VERSION 5.7 ;
  NOWIREEXTENSIONATPIN ON ;
  DIVIDERCHAR "/" ;
  BUSBITCHARS "[]" ;
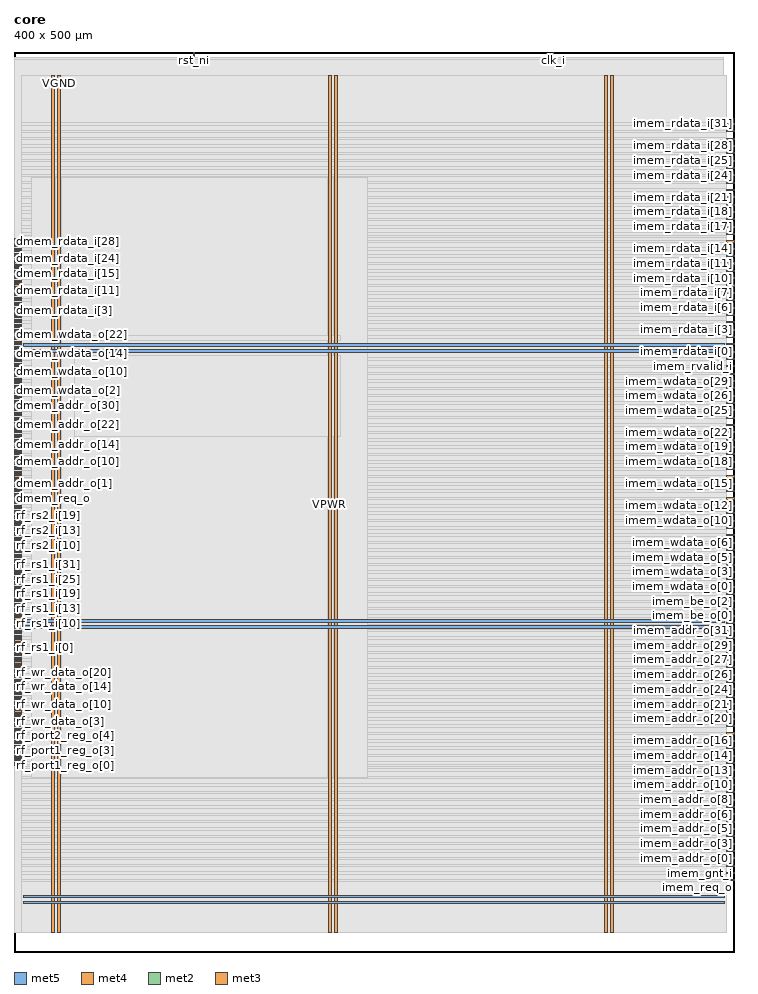
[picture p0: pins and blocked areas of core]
MACRO core
  CLASS BLOCK ;
  FOREIGN core ;
  ORIGIN 0.000 0.000 ;
  SIZE 400.000 BY 500.000 ;
  PIN VGND
    USE GROUND ;
    PORT
      LAYER met5 ;
        RECT 5.280 336.390 394.460 337.990 ;
    END
    PORT
      LAYER met5 ;
        RECT 5.280 183.210 394.460 184.810 ;
    END
    PORT
      LAYER met5 ;
        RECT 5.280 30.030 394.460 31.630 ;
    END
    PORT
      LAYER met4 ;
        RECT 331.540 10.640 333.140 487.120 ;
    END
    PORT
      LAYER met4 ;
        RECT 177.940 10.640 179.540 487.120 ;
    END
    PORT
      LAYER met4 ;
        RECT 24.340 10.640 25.940 487.120 ;
    END
  END VGND
  PIN VPWR
    USE POWER ;
    PORT
      LAYER met5 ;
        RECT 5.280 333.090 394.460 334.690 ;
    END
    PORT
      LAYER met5 ;
        RECT 5.280 179.910 394.460 181.510 ;
    END
    PORT
      LAYER met5 ;
        RECT 5.280 26.730 394.460 28.330 ;
    END
    PORT
      LAYER met4 ;
        RECT 328.240 10.640 329.840 487.120 ;
    END
    PORT
      LAYER met4 ;
        RECT 174.640 10.640 176.240 487.120 ;
    END
    PORT
      LAYER met4 ;
        RECT 21.040 10.640 22.640 487.120 ;
    END
  END VPWR
  PIN clk_i
    PORT
      LAYER met2 ;
        RECT 299.550 496.000 299.830 500.000 ;
    END
  END clk_i
  PIN dmem_addr_o[0]
    PORT
      LAYER met3 ;
        RECT 0.000 258.440 4.000 259.040 ;
    END
  END dmem_addr_o[0]
  PIN dmem_addr_o[10]
    PORT
      LAYER met3 ;
        RECT 0.000 272.040 4.000 272.640 ;
    END
  END dmem_addr_o[10]
  PIN dmem_addr_o[11]
    PORT
      LAYER met3 ;
        RECT 0.000 273.400 4.000 274.000 ;
    END
  END dmem_addr_o[11]
  PIN dmem_addr_o[12]
    PORT
      LAYER met3 ;
        RECT 0.000 274.760 4.000 275.360 ;
    END
  END dmem_addr_o[12]
  PIN dmem_addr_o[13]
    PORT
      LAYER met3 ;
        RECT 0.000 276.120 4.000 276.720 ;
    END
  END dmem_addr_o[13]
  PIN dmem_addr_o[14]
    PORT
      LAYER met3 ;
        RECT 0.000 277.480 4.000 278.080 ;
    END
  END dmem_addr_o[14]
  PIN dmem_addr_o[15]
    PORT
      LAYER met3 ;
        RECT 0.000 278.840 4.000 279.440 ;
    END
  END dmem_addr_o[15]
  PIN dmem_addr_o[16]
    PORT
      LAYER met3 ;
        RECT 0.000 280.200 4.000 280.800 ;
    END
  END dmem_addr_o[16]
  PIN dmem_addr_o[17]
    PORT
      LAYER met3 ;
        RECT 0.000 281.560 4.000 282.160 ;
    END
  END dmem_addr_o[17]
  PIN dmem_addr_o[18]
    PORT
      LAYER met3 ;
        RECT 0.000 282.920 4.000 283.520 ;
    END
  END dmem_addr_o[18]
  PIN dmem_addr_o[19]
    PORT
      LAYER met3 ;
        RECT 0.000 284.280 4.000 284.880 ;
    END
  END dmem_addr_o[19]
  PIN dmem_addr_o[1]
    PORT
      LAYER met3 ;
        RECT 0.000 259.800 4.000 260.400 ;
    END
  END dmem_addr_o[1]
  PIN dmem_addr_o[20]
    PORT
      LAYER met3 ;
        RECT 0.000 285.640 4.000 286.240 ;
    END
  END dmem_addr_o[20]
  PIN dmem_addr_o[21]
    PORT
      LAYER met3 ;
        RECT 0.000 287.000 4.000 287.600 ;
    END
  END dmem_addr_o[21]
  PIN dmem_addr_o[22]
    PORT
      LAYER met3 ;
        RECT 0.000 288.360 4.000 288.960 ;
    END
  END dmem_addr_o[22]
  PIN dmem_addr_o[23]
    PORT
      LAYER met3 ;
        RECT 0.000 289.720 4.000 290.320 ;
    END
  END dmem_addr_o[23]
  PIN dmem_addr_o[24]
    PORT
      LAYER met3 ;
        RECT 0.000 291.080 4.000 291.680 ;
    END
  END dmem_addr_o[24]
  PIN dmem_addr_o[25]
    PORT
      LAYER met3 ;
        RECT 0.000 292.440 4.000 293.040 ;
    END
  END dmem_addr_o[25]
  PIN dmem_addr_o[26]
    PORT
      LAYER met3 ;
        RECT 0.000 293.800 4.000 294.400 ;
    END
  END dmem_addr_o[26]
  PIN dmem_addr_o[27]
    PORT
      LAYER met3 ;
        RECT 0.000 295.160 4.000 295.760 ;
    END
  END dmem_addr_o[27]
  PIN dmem_addr_o[28]
    PORT
      LAYER met3 ;
        RECT 0.000 296.520 4.000 297.120 ;
    END
  END dmem_addr_o[28]
  PIN dmem_addr_o[29]
    PORT
      LAYER met3 ;
        RECT 0.000 297.880 4.000 298.480 ;
    END
  END dmem_addr_o[29]
  PIN dmem_addr_o[2]
    PORT
      LAYER met3 ;
        RECT 0.000 261.160 4.000 261.760 ;
    END
  END dmem_addr_o[2]
  PIN dmem_addr_o[30]
    PORT
      LAYER met3 ;
        RECT 0.000 299.240 4.000 299.840 ;
    END
  END dmem_addr_o[30]
  PIN dmem_addr_o[31]
    PORT
      LAYER met3 ;
        RECT 0.000 300.600 4.000 301.200 ;
    END
  END dmem_addr_o[31]
  PIN dmem_addr_o[3]
    PORT
      LAYER met3 ;
        RECT 0.000 262.520 4.000 263.120 ;
    END
  END dmem_addr_o[3]
  PIN dmem_addr_o[4]
    PORT
      LAYER met3 ;
        RECT 0.000 263.880 4.000 264.480 ;
    END
  END dmem_addr_o[4]
  PIN dmem_addr_o[5]
    PORT
      LAYER met3 ;
        RECT 0.000 265.240 4.000 265.840 ;
    END
  END dmem_addr_o[5]
  PIN dmem_addr_o[6]
    PORT
      LAYER met3 ;
        RECT 0.000 266.600 4.000 267.200 ;
    END
  END dmem_addr_o[6]
  PIN dmem_addr_o[7]
    PORT
      LAYER met3 ;
        RECT 0.000 267.960 4.000 268.560 ;
    END
  END dmem_addr_o[7]
  PIN dmem_addr_o[8]
    PORT
      LAYER met3 ;
        RECT 0.000 269.320 4.000 269.920 ;
    END
  END dmem_addr_o[8]
  PIN dmem_addr_o[9]
    PORT
      LAYER met3 ;
        RECT 0.000 270.680 4.000 271.280 ;
    END
  END dmem_addr_o[9]
  PIN dmem_be_o[0]
    PORT
      LAYER met3 ;
        RECT 0.000 303.320 4.000 303.920 ;
    END
  END dmem_be_o[0]
  PIN dmem_be_o[1]
    PORT
      LAYER met3 ;
        RECT 0.000 304.680 4.000 305.280 ;
    END
  END dmem_be_o[1]
  PIN dmem_be_o[2]
    PORT
      LAYER met3 ;
        RECT 0.000 306.040 4.000 306.640 ;
    END
  END dmem_be_o[2]
  PIN dmem_be_o[3]
    PORT
      LAYER met3 ;
        RECT 0.000 307.400 4.000 308.000 ;
    END
  END dmem_be_o[3]
  PIN dmem_gnt_i
    PORT
      LAYER met3 ;
        RECT 0.000 257.080 4.000 257.680 ;
    END
  END dmem_gnt_i
  PIN dmem_rdata_i[0]
    PORT
      LAYER met3 ;
        RECT 0.000 352.280 4.000 352.880 ;
    END
  END dmem_rdata_i[0]
  PIN dmem_rdata_i[10]
    PORT
      LAYER met3 ;
        RECT 0.000 365.880 4.000 366.480 ;
    END
  END dmem_rdata_i[10]
  PIN dmem_rdata_i[11]
    PORT
      LAYER met3 ;
        RECT 0.000 367.240 4.000 367.840 ;
    END
  END dmem_rdata_i[11]
  PIN dmem_rdata_i[12]
    PORT
      LAYER met3 ;
        RECT 0.000 368.600 4.000 369.200 ;
    END
  END dmem_rdata_i[12]
  PIN dmem_rdata_i[13]
    PORT
      LAYER met3 ;
        RECT 0.000 369.960 4.000 370.560 ;
    END
  END dmem_rdata_i[13]
  PIN dmem_rdata_i[14]
    PORT
      LAYER met3 ;
        RECT 0.000 371.320 4.000 371.920 ;
    END
  END dmem_rdata_i[14]
  PIN dmem_rdata_i[15]
    PORT
      LAYER met3 ;
        RECT 0.000 372.680 4.000 373.280 ;
    END
  END dmem_rdata_i[15]
  PIN dmem_rdata_i[16]
    PORT
      LAYER met3 ;
        RECT 0.000 374.040 4.000 374.640 ;
    END
  END dmem_rdata_i[16]
  PIN dmem_rdata_i[17]
    PORT
      LAYER met3 ;
        RECT 0.000 375.400 4.000 376.000 ;
    END
  END dmem_rdata_i[17]
  PIN dmem_rdata_i[18]
    PORT
      LAYER met3 ;
        RECT 0.000 376.760 4.000 377.360 ;
    END
  END dmem_rdata_i[18]
  PIN dmem_rdata_i[19]
    PORT
      LAYER met3 ;
        RECT 0.000 378.120 4.000 378.720 ;
    END
  END dmem_rdata_i[19]
  PIN dmem_rdata_i[1]
    PORT
      LAYER met3 ;
        RECT 0.000 353.640 4.000 354.240 ;
    END
  END dmem_rdata_i[1]
  PIN dmem_rdata_i[20]
    PORT
      LAYER met3 ;
        RECT 0.000 379.480 4.000 380.080 ;
    END
  END dmem_rdata_i[20]
  PIN dmem_rdata_i[21]
    PORT
      LAYER met3 ;
        RECT 0.000 380.840 4.000 381.440 ;
    END
  END dmem_rdata_i[21]
  PIN dmem_rdata_i[22]
    PORT
      LAYER met3 ;
        RECT 0.000 382.200 4.000 382.800 ;
    END
  END dmem_rdata_i[22]
  PIN dmem_rdata_i[23]
    PORT
      LAYER met3 ;
        RECT 0.000 383.560 4.000 384.160 ;
    END
  END dmem_rdata_i[23]
  PIN dmem_rdata_i[24]
    PORT
      LAYER met3 ;
        RECT 0.000 384.920 4.000 385.520 ;
    END
  END dmem_rdata_i[24]
  PIN dmem_rdata_i[25]
    PORT
      LAYER met3 ;
        RECT 0.000 386.280 4.000 386.880 ;
    END
  END dmem_rdata_i[25]
  PIN dmem_rdata_i[26]
    PORT
      LAYER met3 ;
        RECT 0.000 387.640 4.000 388.240 ;
    END
  END dmem_rdata_i[26]
  PIN dmem_rdata_i[27]
    PORT
      LAYER met3 ;
        RECT 0.000 389.000 4.000 389.600 ;
    END
  END dmem_rdata_i[27]
  PIN dmem_rdata_i[28]
    PORT
      LAYER met3 ;
        RECT 0.000 390.360 4.000 390.960 ;
    END
  END dmem_rdata_i[28]
  PIN dmem_rdata_i[29]
    PORT
      LAYER met3 ;
        RECT 0.000 391.720 4.000 392.320 ;
    END
  END dmem_rdata_i[29]
  PIN dmem_rdata_i[2]
    PORT
      LAYER met3 ;
        RECT 0.000 355.000 4.000 355.600 ;
    END
  END dmem_rdata_i[2]
  PIN dmem_rdata_i[30]
    PORT
      LAYER met3 ;
        RECT 0.000 393.080 4.000 393.680 ;
    END
  END dmem_rdata_i[30]
  PIN dmem_rdata_i[31]
    PORT
      LAYER met3 ;
        RECT 0.000 394.440 4.000 395.040 ;
    END
  END dmem_rdata_i[31]
  PIN dmem_rdata_i[3]
    PORT
      LAYER met3 ;
        RECT 0.000 356.360 4.000 356.960 ;
    END
  END dmem_rdata_i[3]
  PIN dmem_rdata_i[4]
    PORT
      LAYER met3 ;
        RECT 0.000 357.720 4.000 358.320 ;
    END
  END dmem_rdata_i[4]
  PIN dmem_rdata_i[5]
    PORT
      LAYER met3 ;
        RECT 0.000 359.080 4.000 359.680 ;
    END
  END dmem_rdata_i[5]
  PIN dmem_rdata_i[6]
    PORT
      LAYER met3 ;
        RECT 0.000 360.440 4.000 361.040 ;
    END
  END dmem_rdata_i[6]
  PIN dmem_rdata_i[7]
    PORT
      LAYER met3 ;
        RECT 0.000 361.800 4.000 362.400 ;
    END
  END dmem_rdata_i[7]
  PIN dmem_rdata_i[8]
    PORT
      LAYER met3 ;
        RECT 0.000 363.160 4.000 363.760 ;
    END
  END dmem_rdata_i[8]
  PIN dmem_rdata_i[9]
    PORT
      LAYER met3 ;
        RECT 0.000 364.520 4.000 365.120 ;
    END
  END dmem_rdata_i[9]
  PIN dmem_req_o
    PORT
      LAYER met3 ;
        RECT 0.000 255.720 4.000 256.320 ;
    END
  END dmem_req_o
  PIN dmem_rvalid_i
    PORT
      LAYER met3 ;
        RECT 0.000 395.800 4.000 396.400 ;
    END
  END dmem_rvalid_i
  PIN dmem_wdata_o[0]
    PORT
      LAYER met3 ;
        RECT 0.000 308.760 4.000 309.360 ;
    END
  END dmem_wdata_o[0]
  PIN dmem_wdata_o[10]
    PORT
      LAYER met3 ;
        RECT 0.000 322.360 4.000 322.960 ;
    END
  END dmem_wdata_o[10]
  PIN dmem_wdata_o[11]
    PORT
      LAYER met3 ;
        RECT 0.000 323.720 4.000 324.320 ;
    END
  END dmem_wdata_o[11]
  PIN dmem_wdata_o[12]
    PORT
      LAYER met3 ;
        RECT 0.000 325.080 4.000 325.680 ;
    END
  END dmem_wdata_o[12]
  PIN dmem_wdata_o[13]
    PORT
      LAYER met3 ;
        RECT 0.000 326.440 4.000 327.040 ;
    END
  END dmem_wdata_o[13]
  PIN dmem_wdata_o[14]
    PORT
      LAYER met3 ;
        RECT 0.000 327.800 4.000 328.400 ;
    END
  END dmem_wdata_o[14]
  PIN dmem_wdata_o[15]
    PORT
      LAYER met3 ;
        RECT 0.000 329.160 4.000 329.760 ;
    END
  END dmem_wdata_o[15]
  PIN dmem_wdata_o[16]
    PORT
      LAYER met3 ;
        RECT 0.000 330.520 4.000 331.120 ;
    END
  END dmem_wdata_o[16]
  PIN dmem_wdata_o[17]
    PORT
      LAYER met3 ;
        RECT 0.000 331.880 4.000 332.480 ;
    END
  END dmem_wdata_o[17]
  PIN dmem_wdata_o[18]
    PORT
      LAYER met3 ;
        RECT 0.000 333.240 4.000 333.840 ;
    END
  END dmem_wdata_o[18]
  PIN dmem_wdata_o[19]
    PORT
      LAYER met3 ;
        RECT 0.000 334.600 4.000 335.200 ;
    END
  END dmem_wdata_o[19]
  PIN dmem_wdata_o[1]
    PORT
      LAYER met3 ;
        RECT 0.000 310.120 4.000 310.720 ;
    END
  END dmem_wdata_o[1]
  PIN dmem_wdata_o[20]
    PORT
      LAYER met3 ;
        RECT 0.000 335.960 4.000 336.560 ;
    END
  END dmem_wdata_o[20]
  PIN dmem_wdata_o[21]
    PORT
      LAYER met3 ;
        RECT 0.000 337.320 4.000 337.920 ;
    END
  END dmem_wdata_o[21]
  PIN dmem_wdata_o[22]
    PORT
      LAYER met3 ;
        RECT 0.000 338.680 4.000 339.280 ;
    END
  END dmem_wdata_o[22]
  PIN dmem_wdata_o[23]
    PORT
      LAYER met3 ;
        RECT 0.000 340.040 4.000 340.640 ;
    END
  END dmem_wdata_o[23]
  PIN dmem_wdata_o[24]
    PORT
      LAYER met3 ;
        RECT 0.000 341.400 4.000 342.000 ;
    END
  END dmem_wdata_o[24]
  PIN dmem_wdata_o[25]
    PORT
      LAYER met3 ;
        RECT 0.000 342.760 4.000 343.360 ;
    END
  END dmem_wdata_o[25]
  PIN dmem_wdata_o[26]
    PORT
      LAYER met3 ;
        RECT 0.000 344.120 4.000 344.720 ;
    END
  END dmem_wdata_o[26]
  PIN dmem_wdata_o[27]
    PORT
      LAYER met3 ;
        RECT 0.000 345.480 4.000 346.080 ;
    END
  END dmem_wdata_o[27]
  PIN dmem_wdata_o[28]
    PORT
      LAYER met3 ;
        RECT 0.000 346.840 4.000 347.440 ;
    END
  END dmem_wdata_o[28]
  PIN dmem_wdata_o[29]
    PORT
      LAYER met3 ;
        RECT 0.000 348.200 4.000 348.800 ;
    END
  END dmem_wdata_o[29]
  PIN dmem_wdata_o[2]
    PORT
      LAYER met3 ;
        RECT 0.000 311.480 4.000 312.080 ;
    END
  END dmem_wdata_o[2]
  PIN dmem_wdata_o[30]
    PORT
      LAYER met3 ;
        RECT 0.000 349.560 4.000 350.160 ;
    END
  END dmem_wdata_o[30]
  PIN dmem_wdata_o[31]
    PORT
      LAYER met3 ;
        RECT 0.000 350.920 4.000 351.520 ;
    END
  END dmem_wdata_o[31]
  PIN dmem_wdata_o[3]
    PORT
      LAYER met3 ;
        RECT 0.000 312.840 4.000 313.440 ;
    END
  END dmem_wdata_o[3]
  PIN dmem_wdata_o[4]
    PORT
      LAYER met3 ;
        RECT 0.000 314.200 4.000 314.800 ;
    END
  END dmem_wdata_o[4]
  PIN dmem_wdata_o[5]
    PORT
      LAYER met3 ;
        RECT 0.000 315.560 4.000 316.160 ;
    END
  END dmem_wdata_o[5]
  PIN dmem_wdata_o[6]
    PORT
      LAYER met3 ;
        RECT 0.000 316.920 4.000 317.520 ;
    END
  END dmem_wdata_o[6]
  PIN dmem_wdata_o[7]
    PORT
      LAYER met3 ;
        RECT 0.000 318.280 4.000 318.880 ;
    END
  END dmem_wdata_o[7]
  PIN dmem_wdata_o[8]
    PORT
      LAYER met3 ;
        RECT 0.000 319.640 4.000 320.240 ;
    END
  END dmem_wdata_o[8]
  PIN dmem_wdata_o[9]
    PORT
      LAYER met3 ;
        RECT 0.000 321.000 4.000 321.600 ;
    END
  END dmem_wdata_o[9]
  PIN dmem_we_o
    PORT
      LAYER met3 ;
        RECT 0.000 301.960 4.000 302.560 ;
    END
  END dmem_we_o
  PIN imem_addr_o[0]
    PORT
      LAYER met3 ;
        RECT 396.000 47.640 400.000 48.240 ;
    END
  END imem_addr_o[0]
  PIN imem_addr_o[10]
    PORT
      LAYER met3 ;
        RECT 396.000 88.440 400.000 89.040 ;
    END
  END imem_addr_o[10]
  PIN imem_addr_o[11]
    PORT
      LAYER met3 ;
        RECT 396.000 92.520 400.000 93.120 ;
    END
  END imem_addr_o[11]
  PIN imem_addr_o[12]
    PORT
      LAYER met3 ;
        RECT 396.000 96.600 400.000 97.200 ;
    END
  END imem_addr_o[12]
  PIN imem_addr_o[13]
    PORT
      LAYER met3 ;
        RECT 396.000 100.680 400.000 101.280 ;
    END
  END imem_addr_o[13]
  PIN imem_addr_o[14]
    PORT
      LAYER met3 ;
        RECT 396.000 104.760 400.000 105.360 ;
    END
  END imem_addr_o[14]
  PIN imem_addr_o[15]
    PORT
      LAYER met3 ;
        RECT 396.000 108.840 400.000 109.440 ;
    END
  END imem_addr_o[15]
  PIN imem_addr_o[16]
    PORT
      LAYER met3 ;
        RECT 396.000 112.920 400.000 113.520 ;
    END
  END imem_addr_o[16]
  PIN imem_addr_o[17]
    PORT
      LAYER met3 ;
        RECT 396.000 117.000 400.000 117.600 ;
    END
  END imem_addr_o[17]
  PIN imem_addr_o[18]
    PORT
      LAYER met3 ;
        RECT 396.000 121.080 400.000 121.680 ;
    END
  END imem_addr_o[18]
  PIN imem_addr_o[19]
    PORT
      LAYER met3 ;
        RECT 396.000 125.160 400.000 125.760 ;
    END
  END imem_addr_o[19]
  PIN imem_addr_o[1]
    PORT
      LAYER met3 ;
        RECT 396.000 51.720 400.000 52.320 ;
    END
  END imem_addr_o[1]
  PIN imem_addr_o[20]
    PORT
      LAYER met3 ;
        RECT 396.000 129.240 400.000 129.840 ;
    END
  END imem_addr_o[20]
  PIN imem_addr_o[21]
    PORT
      LAYER met3 ;
        RECT 396.000 133.320 400.000 133.920 ;
    END
  END imem_addr_o[21]
  PIN imem_addr_o[22]
    PORT
      LAYER met3 ;
        RECT 396.000 137.400 400.000 138.000 ;
    END
  END imem_addr_o[22]
  PIN imem_addr_o[23]
    PORT
      LAYER met3 ;
        RECT 396.000 141.480 400.000 142.080 ;
    END
  END imem_addr_o[23]
  PIN imem_addr_o[24]
    PORT
      LAYER met3 ;
        RECT 396.000 145.560 400.000 146.160 ;
    END
  END imem_addr_o[24]
  PIN imem_addr_o[25]
    PORT
      LAYER met3 ;
        RECT 396.000 149.640 400.000 150.240 ;
    END
  END imem_addr_o[25]
  PIN imem_addr_o[26]
    PORT
      LAYER met3 ;
        RECT 396.000 153.720 400.000 154.320 ;
    END
  END imem_addr_o[26]
  PIN imem_addr_o[27]
    PORT
      LAYER met3 ;
        RECT 396.000 157.800 400.000 158.400 ;
    END
  END imem_addr_o[27]
  PIN imem_addr_o[28]
    PORT
      LAYER met3 ;
        RECT 396.000 161.880 400.000 162.480 ;
    END
  END imem_addr_o[28]
  PIN imem_addr_o[29]
    PORT
      LAYER met3 ;
        RECT 396.000 165.960 400.000 166.560 ;
    END
  END imem_addr_o[29]
  PIN imem_addr_o[2]
    PORT
      LAYER met3 ;
        RECT 396.000 55.800 400.000 56.400 ;
    END
  END imem_addr_o[2]
  PIN imem_addr_o[30]
    PORT
      LAYER met3 ;
        RECT 396.000 170.040 400.000 170.640 ;
    END
  END imem_addr_o[30]
  PIN imem_addr_o[31]
    PORT
      LAYER met3 ;
        RECT 396.000 174.120 400.000 174.720 ;
    END
  END imem_addr_o[31]
  PIN imem_addr_o[3]
    PORT
      LAYER met3 ;
        RECT 396.000 59.880 400.000 60.480 ;
    END
  END imem_addr_o[3]
  PIN imem_addr_o[4]
    PORT
      LAYER met3 ;
        RECT 396.000 63.960 400.000 64.560 ;
    END
  END imem_addr_o[4]
  PIN imem_addr_o[5]
    PORT
      LAYER met3 ;
        RECT 396.000 68.040 400.000 68.640 ;
    END
  END imem_addr_o[5]
  PIN imem_addr_o[6]
    PORT
      LAYER met3 ;
        RECT 396.000 72.120 400.000 72.720 ;
    END
  END imem_addr_o[6]
  PIN imem_addr_o[7]
    PORT
      LAYER met3 ;
        RECT 396.000 76.200 400.000 76.800 ;
    END
  END imem_addr_o[7]
  PIN imem_addr_o[8]
    PORT
      LAYER met3 ;
        RECT 396.000 80.280 400.000 80.880 ;
    END
  END imem_addr_o[8]
  PIN imem_addr_o[9]
    PORT
      LAYER met3 ;
        RECT 396.000 84.360 400.000 84.960 ;
    END
  END imem_addr_o[9]
  PIN imem_be_o[0]
    PORT
      LAYER met3 ;
        RECT 396.000 182.280 400.000 182.880 ;
    END
  END imem_be_o[0]
  PIN imem_be_o[1]
    PORT
      LAYER met3 ;
        RECT 396.000 186.360 400.000 186.960 ;
    END
  END imem_be_o[1]
  PIN imem_be_o[2]
    PORT
      LAYER met3 ;
        RECT 396.000 190.440 400.000 191.040 ;
    END
  END imem_be_o[2]
  PIN imem_be_o[3]
    PORT
      LAYER met3 ;
        RECT 396.000 194.520 400.000 195.120 ;
    END
  END imem_be_o[3]
  PIN imem_gnt_i
    PORT
      LAYER met3 ;
        RECT 396.000 43.560 400.000 44.160 ;
    END
  END imem_gnt_i
  PIN imem_rdata_i[0]
    PORT
      LAYER met3 ;
        RECT 396.000 333.240 400.000 333.840 ;
    END
  END imem_rdata_i[0]
  PIN imem_rdata_i[10]
    PORT
      LAYER met3 ;
        RECT 396.000 374.040 400.000 374.640 ;
    END
  END imem_rdata_i[10]
  PIN imem_rdata_i[11]
    PORT
      LAYER met3 ;
        RECT 396.000 378.120 400.000 378.720 ;
    END
  END imem_rdata_i[11]
  PIN imem_rdata_i[12]
    PORT
      LAYER met3 ;
        RECT 396.000 382.200 400.000 382.800 ;
    END
  END imem_rdata_i[12]
  PIN imem_rdata_i[13]
    PORT
      LAYER met3 ;
        RECT 396.000 386.280 400.000 386.880 ;
    END
  END imem_rdata_i[13]
  PIN imem_rdata_i[14]
    PORT
      LAYER met3 ;
        RECT 396.000 390.360 400.000 390.960 ;
    END
  END imem_rdata_i[14]
  PIN imem_rdata_i[15]
    PORT
      LAYER met3 ;
        RECT 396.000 394.440 400.000 395.040 ;
    END
  END imem_rdata_i[15]
  PIN imem_rdata_i[16]
    PORT
      LAYER met3 ;
        RECT 396.000 398.520 400.000 399.120 ;
    END
  END imem_rdata_i[16]
  PIN imem_rdata_i[17]
    PORT
      LAYER met3 ;
        RECT 396.000 402.600 400.000 403.200 ;
    END
  END imem_rdata_i[17]
  PIN imem_rdata_i[18]
    PORT
      LAYER met3 ;
        RECT 396.000 406.680 400.000 407.280 ;
    END
  END imem_rdata_i[18]
  PIN imem_rdata_i[19]
    PORT
      LAYER met3 ;
        RECT 396.000 410.760 400.000 411.360 ;
    END
  END imem_rdata_i[19]
  PIN imem_rdata_i[1]
    PORT
      LAYER met3 ;
        RECT 396.000 337.320 400.000 337.920 ;
    END
  END imem_rdata_i[1]
  PIN imem_rdata_i[20]
    PORT
      LAYER met3 ;
        RECT 396.000 414.840 400.000 415.440 ;
    END
  END imem_rdata_i[20]
  PIN imem_rdata_i[21]
    PORT
      LAYER met3 ;
        RECT 396.000 418.920 400.000 419.520 ;
    END
  END imem_rdata_i[21]
  PIN imem_rdata_i[22]
    PORT
      LAYER met3 ;
        RECT 396.000 423.000 400.000 423.600 ;
    END
  END imem_rdata_i[22]
  PIN imem_rdata_i[23]
    PORT
      LAYER met3 ;
        RECT 396.000 427.080 400.000 427.680 ;
    END
  END imem_rdata_i[23]
  PIN imem_rdata_i[24]
    PORT
      LAYER met3 ;
        RECT 396.000 431.160 400.000 431.760 ;
    END
  END imem_rdata_i[24]
  PIN imem_rdata_i[25]
    PORT
      LAYER met3 ;
        RECT 396.000 435.240 400.000 435.840 ;
    END
  END imem_rdata_i[25]
  PIN imem_rdata_i[26]
    PORT
      LAYER met3 ;
        RECT 396.000 439.320 400.000 439.920 ;
    END
  END imem_rdata_i[26]
  PIN imem_rdata_i[27]
    PORT
      LAYER met3 ;
        RECT 396.000 443.400 400.000 444.000 ;
    END
  END imem_rdata_i[27]
  PIN imem_rdata_i[28]
    PORT
      LAYER met3 ;
        RECT 396.000 447.480 400.000 448.080 ;
    END
  END imem_rdata_i[28]
  PIN imem_rdata_i[29]
    PORT
      LAYER met3 ;
        RECT 396.000 451.560 400.000 452.160 ;
    END
  END imem_rdata_i[29]
  PIN imem_rdata_i[2]
    PORT
      LAYER met3 ;
        RECT 396.000 341.400 400.000 342.000 ;
    END
  END imem_rdata_i[2]
  PIN imem_rdata_i[30]
    PORT
      LAYER met3 ;
        RECT 396.000 455.640 400.000 456.240 ;
    END
  END imem_rdata_i[30]
  PIN imem_rdata_i[31]
    PORT
      LAYER met3 ;
        RECT 396.000 459.720 400.000 460.320 ;
    END
  END imem_rdata_i[31]
  PIN imem_rdata_i[3]
    PORT
      LAYER met3 ;
        RECT 396.000 345.480 400.000 346.080 ;
    END
  END imem_rdata_i[3]
  PIN imem_rdata_i[4]
    PORT
      LAYER met3 ;
        RECT 396.000 349.560 400.000 350.160 ;
    END
  END imem_rdata_i[4]
  PIN imem_rdata_i[5]
    PORT
      LAYER met3 ;
        RECT 396.000 353.640 400.000 354.240 ;
    END
  END imem_rdata_i[5]
  PIN imem_rdata_i[6]
    PORT
      LAYER met3 ;
        RECT 396.000 357.720 400.000 358.320 ;
    END
  END imem_rdata_i[6]
  PIN imem_rdata_i[7]
    PORT
      LAYER met3 ;
        RECT 396.000 361.800 400.000 362.400 ;
    END
  END imem_rdata_i[7]
  PIN imem_rdata_i[8]
    PORT
      LAYER met3 ;
        RECT 396.000 365.880 400.000 366.480 ;
    END
  END imem_rdata_i[8]
  PIN imem_rdata_i[9]
    PORT
      LAYER met3 ;
        RECT 396.000 369.960 400.000 370.560 ;
    END
  END imem_rdata_i[9]
  PIN imem_req_o
    PORT
      LAYER met3 ;
        RECT 396.000 39.480 400.000 40.080 ;
    END
  END imem_req_o
  PIN imem_rvalid_i
    PORT
      LAYER met3 ;
        RECT 396.000 329.160 400.000 329.760 ;
    END
  END imem_rvalid_i
  PIN imem_wdata_o[0]
    PORT
      LAYER met3 ;
        RECT 396.000 198.600 400.000 199.200 ;
    END
  END imem_wdata_o[0]
  PIN imem_wdata_o[10]
    PORT
      LAYER met3 ;
        RECT 396.000 239.400 400.000 240.000 ;
    END
  END imem_wdata_o[10]
  PIN imem_wdata_o[11]
    PORT
      LAYER met3 ;
        RECT 396.000 243.480 400.000 244.080 ;
    END
  END imem_wdata_o[11]
  PIN imem_wdata_o[12]
    PORT
      LAYER met3 ;
        RECT 396.000 247.560 400.000 248.160 ;
    END
  END imem_wdata_o[12]
  PIN imem_wdata_o[13]
    PORT
      LAYER met3 ;
        RECT 396.000 251.640 400.000 252.240 ;
    END
  END imem_wdata_o[13]
  PIN imem_wdata_o[14]
    PORT
      LAYER met3 ;
        RECT 396.000 255.720 400.000 256.320 ;
    END
  END imem_wdata_o[14]
  PIN imem_wdata_o[15]
    PORT
      LAYER met3 ;
        RECT 396.000 259.800 400.000 260.400 ;
    END
  END imem_wdata_o[15]
  PIN imem_wdata_o[16]
    PORT
      LAYER met3 ;
        RECT 396.000 263.880 400.000 264.480 ;
    END
  END imem_wdata_o[16]
  PIN imem_wdata_o[17]
    PORT
      LAYER met3 ;
        RECT 396.000 267.960 400.000 268.560 ;
    END
  END imem_wdata_o[17]
  PIN imem_wdata_o[18]
    PORT
      LAYER met3 ;
        RECT 396.000 272.040 400.000 272.640 ;
    END
  END imem_wdata_o[18]
  PIN imem_wdata_o[19]
    PORT
      LAYER met3 ;
        RECT 396.000 276.120 400.000 276.720 ;
    END
  END imem_wdata_o[19]
  PIN imem_wdata_o[1]
    PORT
      LAYER met3 ;
        RECT 396.000 202.680 400.000 203.280 ;
    END
  END imem_wdata_o[1]
  PIN imem_wdata_o[20]
    PORT
      LAYER met3 ;
        RECT 396.000 280.200 400.000 280.800 ;
    END
  END imem_wdata_o[20]
  PIN imem_wdata_o[21]
    PORT
      LAYER met3 ;
        RECT 396.000 284.280 400.000 284.880 ;
    END
  END imem_wdata_o[21]
  PIN imem_wdata_o[22]
    PORT
      LAYER met3 ;
        RECT 396.000 288.360 400.000 288.960 ;
    END
  END imem_wdata_o[22]
  PIN imem_wdata_o[23]
    PORT
      LAYER met3 ;
        RECT 396.000 292.440 400.000 293.040 ;
    END
  END imem_wdata_o[23]
  PIN imem_wdata_o[24]
    PORT
      LAYER met3 ;
        RECT 396.000 296.520 400.000 297.120 ;
    END
  END imem_wdata_o[24]
  PIN imem_wdata_o[25]
    PORT
      LAYER met3 ;
        RECT 396.000 300.600 400.000 301.200 ;
    END
  END imem_wdata_o[25]
  PIN imem_wdata_o[26]
    PORT
      LAYER met3 ;
        RECT 396.000 304.680 400.000 305.280 ;
    END
  END imem_wdata_o[26]
  PIN imem_wdata_o[27]
    PORT
      LAYER met3 ;
        RECT 396.000 308.760 400.000 309.360 ;
    END
  END imem_wdata_o[27]
  PIN imem_wdata_o[28]
    PORT
      LAYER met3 ;
        RECT 396.000 312.840 400.000 313.440 ;
    END
  END imem_wdata_o[28]
  PIN imem_wdata_o[29]
    PORT
      LAYER met3 ;
        RECT 396.000 316.920 400.000 317.520 ;
    END
  END imem_wdata_o[29]
  PIN imem_wdata_o[2]
    PORT
      LAYER met3 ;
        RECT 396.000 206.760 400.000 207.360 ;
    END
  END imem_wdata_o[2]
  PIN imem_wdata_o[30]
    PORT
      LAYER met3 ;
        RECT 396.000 321.000 400.000 321.600 ;
    END
  END imem_wdata_o[30]
  PIN imem_wdata_o[31]
    PORT
      LAYER met3 ;
        RECT 396.000 325.080 400.000 325.680 ;
    END
  END imem_wdata_o[31]
  PIN imem_wdata_o[3]
    PORT
      LAYER met3 ;
        RECT 396.000 210.840 400.000 211.440 ;
    END
  END imem_wdata_o[3]
  PIN imem_wdata_o[4]
    PORT
      LAYER met3 ;
        RECT 396.000 214.920 400.000 215.520 ;
    END
  END imem_wdata_o[4]
  PIN imem_wdata_o[5]
    PORT
      LAYER met3 ;
        RECT 396.000 219.000 400.000 219.600 ;
    END
  END imem_wdata_o[5]
  PIN imem_wdata_o[6]
    PORT
      LAYER met3 ;
        RECT 396.000 223.080 400.000 223.680 ;
    END
  END imem_wdata_o[6]
  PIN imem_wdata_o[7]
    PORT
      LAYER met3 ;
        RECT 396.000 227.160 400.000 227.760 ;
    END
  END imem_wdata_o[7]
  PIN imem_wdata_o[8]
    PORT
      LAYER met3 ;
        RECT 396.000 231.240 400.000 231.840 ;
    END
  END imem_wdata_o[8]
  PIN imem_wdata_o[9]
    PORT
      LAYER met3 ;
        RECT 396.000 235.320 400.000 235.920 ;
    END
  END imem_wdata_o[9]
  PIN imem_we_o
    PORT
      LAYER met3 ;
        RECT 396.000 178.200 400.000 178.800 ;
    END
  END imem_we_o
  PIN rf_port1_reg_o[0]
    PORT
      LAYER met3 ;
        RECT 0.000 103.400 4.000 104.000 ;
    END
  END rf_port1_reg_o[0]
  PIN rf_port1_reg_o[1]
    PORT
      LAYER met3 ;
        RECT 0.000 104.760 4.000 105.360 ;
    END
  END rf_port1_reg_o[1]
  PIN rf_port1_reg_o[2]
    PORT
      LAYER met3 ;
        RECT 0.000 106.120 4.000 106.720 ;
    END
  END rf_port1_reg_o[2]
  PIN rf_port1_reg_o[3]
    PORT
      LAYER met3 ;
        RECT 0.000 107.480 4.000 108.080 ;
    END
  END rf_port1_reg_o[3]
  PIN rf_port1_reg_o[4]
    PORT
      LAYER met3 ;
        RECT 0.000 108.840 4.000 109.440 ;
    END
  END rf_port1_reg_o[4]
  PIN rf_port2_reg_o[0]
    PORT
      LAYER met3 ;
        RECT 0.000 110.200 4.000 110.800 ;
    END
  END rf_port2_reg_o[0]
  PIN rf_port2_reg_o[1]
    PORT
      LAYER met3 ;
        RECT 0.000 111.560 4.000 112.160 ;
    END
  END rf_port2_reg_o[1]
  PIN rf_port2_reg_o[2]
    PORT
      LAYER met3 ;
        RECT 0.000 112.920 4.000 113.520 ;
    END
  END rf_port2_reg_o[2]
  PIN rf_port2_reg_o[3]
    PORT
      LAYER met3 ;
        RECT 0.000 114.280 4.000 114.880 ;
    END
  END rf_port2_reg_o[3]
  PIN rf_port2_reg_o[4]
    PORT
      LAYER met3 ;
        RECT 0.000 115.640 4.000 116.240 ;
    END
  END rf_port2_reg_o[4]
  PIN rf_rs1_i[0]
    PORT
      LAYER met3 ;
        RECT 0.000 168.680 4.000 169.280 ;
    END
  END rf_rs1_i[0]
  PIN rf_rs1_i[10]
    PORT
      LAYER met3 ;
        RECT 0.000 182.280 4.000 182.880 ;
    END
  END rf_rs1_i[10]
  PIN rf_rs1_i[11]
    PORT
      LAYER met3 ;
        RECT 0.000 183.640 4.000 184.240 ;
    END
  END rf_rs1_i[11]
  PIN rf_rs1_i[12]
    PORT
      LAYER met3 ;
        RECT 0.000 185.000 4.000 185.600 ;
    END
  END rf_rs1_i[12]
  PIN rf_rs1_i[13]
    PORT
      LAYER met3 ;
        RECT 0.000 186.360 4.000 186.960 ;
    END
  END rf_rs1_i[13]
  PIN rf_rs1_i[14]
    PORT
      LAYER met3 ;
        RECT 0.000 187.720 4.000 188.320 ;
    END
  END rf_rs1_i[14]
  PIN rf_rs1_i[15]
    PORT
      LAYER met3 ;
        RECT 0.000 189.080 4.000 189.680 ;
    END
  END rf_rs1_i[15]
  PIN rf_rs1_i[16]
    PORT
      LAYER met3 ;
        RECT 0.000 190.440 4.000 191.040 ;
    END
  END rf_rs1_i[16]
  PIN rf_rs1_i[17]
    PORT
      LAYER met3 ;
        RECT 0.000 191.800 4.000 192.400 ;
    END
  END rf_rs1_i[17]
  PIN rf_rs1_i[18]
    PORT
      LAYER met3 ;
        RECT 0.000 193.160 4.000 193.760 ;
    END
  END rf_rs1_i[18]
  PIN rf_rs1_i[19]
    PORT
      LAYER met3 ;
        RECT 0.000 194.520 4.000 195.120 ;
    END
  END rf_rs1_i[19]
  PIN rf_rs1_i[1]
    PORT
      LAYER met3 ;
        RECT 0.000 170.040 4.000 170.640 ;
    END
  END rf_rs1_i[1]
  PIN rf_rs1_i[20]
    PORT
      LAYER met3 ;
        RECT 0.000 195.880 4.000 196.480 ;
    END
  END rf_rs1_i[20]
  PIN rf_rs1_i[21]
    PORT
      LAYER met3 ;
        RECT 0.000 197.240 4.000 197.840 ;
    END
  END rf_rs1_i[21]
  PIN rf_rs1_i[22]
    PORT
      LAYER met3 ;
        RECT 0.000 198.600 4.000 199.200 ;
    END
  END rf_rs1_i[22]
  PIN rf_rs1_i[23]
    PORT
      LAYER met3 ;
        RECT 0.000 199.960 4.000 200.560 ;
    END
  END rf_rs1_i[23]
  PIN rf_rs1_i[24]
    PORT
      LAYER met3 ;
        RECT 0.000 201.320 4.000 201.920 ;
    END
  END rf_rs1_i[24]
  PIN rf_rs1_i[25]
    PORT
      LAYER met3 ;
        RECT 0.000 202.680 4.000 203.280 ;
    END
  END rf_rs1_i[25]
  PIN rf_rs1_i[26]
    PORT
      LAYER met3 ;
        RECT 0.000 204.040 4.000 204.640 ;
    END
  END rf_rs1_i[26]
  PIN rf_rs1_i[27]
    PORT
      LAYER met3 ;
        RECT 0.000 205.400 4.000 206.000 ;
    END
  END rf_rs1_i[27]
  PIN rf_rs1_i[28]
    PORT
      LAYER met3 ;
        RECT 0.000 206.760 4.000 207.360 ;
    END
  END rf_rs1_i[28]
  PIN rf_rs1_i[29]
    PORT
      LAYER met3 ;
        RECT 0.000 208.120 4.000 208.720 ;
    END
  END rf_rs1_i[29]
  PIN rf_rs1_i[2]
    PORT
      LAYER met3 ;
        RECT 0.000 171.400 4.000 172.000 ;
    END
  END rf_rs1_i[2]
  PIN rf_rs1_i[30]
    PORT
      LAYER met3 ;
        RECT 0.000 209.480 4.000 210.080 ;
    END
  END rf_rs1_i[30]
  PIN rf_rs1_i[31]
    PORT
      LAYER met3 ;
        RECT 0.000 210.840 4.000 211.440 ;
    END
  END rf_rs1_i[31]
  PIN rf_rs1_i[3]
    PORT
      LAYER met3 ;
        RECT 0.000 172.760 4.000 173.360 ;
    END
  END rf_rs1_i[3]
  PIN rf_rs1_i[4]
    PORT
      LAYER met3 ;
        RECT 0.000 174.120 4.000 174.720 ;
    END
  END rf_rs1_i[4]
  PIN rf_rs1_i[5]
    PORT
      LAYER met3 ;
        RECT 0.000 175.480 4.000 176.080 ;
    END
  END rf_rs1_i[5]
  PIN rf_rs1_i[6]
    PORT
      LAYER met3 ;
        RECT 0.000 176.840 4.000 177.440 ;
    END
  END rf_rs1_i[6]
  PIN rf_rs1_i[7]
    PORT
      LAYER met3 ;
        RECT 0.000 178.200 4.000 178.800 ;
    END
  END rf_rs1_i[7]
  PIN rf_rs1_i[8]
    PORT
      LAYER met3 ;
        RECT 0.000 179.560 4.000 180.160 ;
    END
  END rf_rs1_i[8]
  PIN rf_rs1_i[9]
    PORT
      LAYER met3 ;
        RECT 0.000 180.920 4.000 181.520 ;
    END
  END rf_rs1_i[9]
  PIN rf_rs2_i[0]
    PORT
      LAYER met3 ;
        RECT 0.000 212.200 4.000 212.800 ;
    END
  END rf_rs2_i[0]
  PIN rf_rs2_i[10]
    PORT
      LAYER met3 ;
        RECT 0.000 225.800 4.000 226.400 ;
    END
  END rf_rs2_i[10]
  PIN rf_rs2_i[11]
    PORT
      LAYER met3 ;
        RECT 0.000 227.160 4.000 227.760 ;
    END
  END rf_rs2_i[11]
  PIN rf_rs2_i[12]
    PORT
      LAYER met3 ;
        RECT 0.000 228.520 4.000 229.120 ;
    END
  END rf_rs2_i[12]
  PIN rf_rs2_i[13]
    PORT
      LAYER met3 ;
        RECT 0.000 229.880 4.000 230.480 ;
    END
  END rf_rs2_i[13]
  PIN rf_rs2_i[14]
    PORT
      LAYER met3 ;
        RECT 0.000 231.240 4.000 231.840 ;
    END
  END rf_rs2_i[14]
  PIN rf_rs2_i[15]
    PORT
      LAYER met3 ;
        RECT 0.000 232.600 4.000 233.200 ;
    END
  END rf_rs2_i[15]
  PIN rf_rs2_i[16]
    PORT
      LAYER met3 ;
        RECT 0.000 233.960 4.000 234.560 ;
    END
  END rf_rs2_i[16]
  PIN rf_rs2_i[17]
    PORT
      LAYER met3 ;
        RECT 0.000 235.320 4.000 235.920 ;
    END
  END rf_rs2_i[17]
  PIN rf_rs2_i[18]
    PORT
      LAYER met3 ;
        RECT 0.000 236.680 4.000 237.280 ;
    END
  END rf_rs2_i[18]
  PIN rf_rs2_i[19]
    PORT
      LAYER met3 ;
        RECT 0.000 238.040 4.000 238.640 ;
    END
  END rf_rs2_i[19]
  PIN rf_rs2_i[1]
    PORT
      LAYER met3 ;
        RECT 0.000 213.560 4.000 214.160 ;
    END
  END rf_rs2_i[1]
  PIN rf_rs2_i[20]
    PORT
      LAYER met3 ;
        RECT 0.000 239.400 4.000 240.000 ;
    END
  END rf_rs2_i[20]
  PIN rf_rs2_i[21]
    PORT
      LAYER met3 ;
        RECT 0.000 240.760 4.000 241.360 ;
    END
  END rf_rs2_i[21]
  PIN rf_rs2_i[22]
    PORT
      LAYER met3 ;
        RECT 0.000 242.120 4.000 242.720 ;
    END
  END rf_rs2_i[22]
  PIN rf_rs2_i[23]
    PORT
      LAYER met3 ;
        RECT 0.000 243.480 4.000 244.080 ;
    END
  END rf_rs2_i[23]
  PIN rf_rs2_i[24]
    PORT
      LAYER met3 ;
        RECT 0.000 244.840 4.000 245.440 ;
    END
  END rf_rs2_i[24]
  PIN rf_rs2_i[25]
    PORT
      LAYER met3 ;
        RECT 0.000 246.200 4.000 246.800 ;
    END
  END rf_rs2_i[25]
  PIN rf_rs2_i[26]
    PORT
      LAYER met3 ;
        RECT 0.000 247.560 4.000 248.160 ;
    END
  END rf_rs2_i[26]
  PIN rf_rs2_i[27]
    PORT
      LAYER met3 ;
        RECT 0.000 248.920 4.000 249.520 ;
    END
  END rf_rs2_i[27]
  PIN rf_rs2_i[28]
    PORT
      LAYER met3 ;
        RECT 0.000 250.280 4.000 250.880 ;
    END
  END rf_rs2_i[28]
  PIN rf_rs2_i[29]
    PORT
      LAYER met3 ;
        RECT 0.000 251.640 4.000 252.240 ;
    END
  END rf_rs2_i[29]
  PIN rf_rs2_i[2]
    PORT
      LAYER met3 ;
        RECT 0.000 214.920 4.000 215.520 ;
    END
  END rf_rs2_i[2]
  PIN rf_rs2_i[30]
    PORT
      LAYER met3 ;
        RECT 0.000 253.000 4.000 253.600 ;
    END
  END rf_rs2_i[30]
  PIN rf_rs2_i[31]
    PORT
      LAYER met3 ;
        RECT 0.000 254.360 4.000 254.960 ;
    END
  END rf_rs2_i[31]
  PIN rf_rs2_i[3]
    PORT
      LAYER met3 ;
        RECT 0.000 216.280 4.000 216.880 ;
    END
  END rf_rs2_i[3]
  PIN rf_rs2_i[4]
    PORT
      LAYER met3 ;
        RECT 0.000 217.640 4.000 218.240 ;
    END
  END rf_rs2_i[4]
  PIN rf_rs2_i[5]
    PORT
      LAYER met3 ;
        RECT 0.000 219.000 4.000 219.600 ;
    END
  END rf_rs2_i[5]
  PIN rf_rs2_i[6]
    PORT
      LAYER met3 ;
        RECT 0.000 220.360 4.000 220.960 ;
    END
  END rf_rs2_i[6]
  PIN rf_rs2_i[7]
    PORT
      LAYER met3 ;
        RECT 0.000 221.720 4.000 222.320 ;
    END
  END rf_rs2_i[7]
  PIN rf_rs2_i[8]
    PORT
      LAYER met3 ;
        RECT 0.000 223.080 4.000 223.680 ;
    END
  END rf_rs2_i[8]
  PIN rf_rs2_i[9]
    PORT
      LAYER met3 ;
        RECT 0.000 224.440 4.000 225.040 ;
    END
  END rf_rs2_i[9]
  PIN rf_wr_data_o[0]
    PORT
      LAYER met3 ;
        RECT 0.000 123.800 4.000 124.400 ;
    END
  END rf_wr_data_o[0]
  PIN rf_wr_data_o[10]
    PORT
      LAYER met3 ;
        RECT 0.000 137.400 4.000 138.000 ;
    END
  END rf_wr_data_o[10]
  PIN rf_wr_data_o[11]
    PORT
      LAYER met3 ;
        RECT 0.000 138.760 4.000 139.360 ;
    END
  END rf_wr_data_o[11]
  PIN rf_wr_data_o[12]
    PORT
      LAYER met3 ;
        RECT 0.000 140.120 4.000 140.720 ;
    END
  END rf_wr_data_o[12]
  PIN rf_wr_data_o[13]
    PORT
      LAYER met3 ;
        RECT 0.000 141.480 4.000 142.080 ;
    END
  END rf_wr_data_o[13]
  PIN rf_wr_data_o[14]
    PORT
      LAYER met3 ;
        RECT 0.000 142.840 4.000 143.440 ;
    END
  END rf_wr_data_o[14]
  PIN rf_wr_data_o[15]
    PORT
      LAYER met3 ;
        RECT 0.000 144.200 4.000 144.800 ;
    END
  END rf_wr_data_o[15]
  PIN rf_wr_data_o[16]
    PORT
      LAYER met3 ;
        RECT 0.000 145.560 4.000 146.160 ;
    END
  END rf_wr_data_o[16]
  PIN rf_wr_data_o[17]
    PORT
      LAYER met3 ;
        RECT 0.000 146.920 4.000 147.520 ;
    END
  END rf_wr_data_o[17]
  PIN rf_wr_data_o[18]
    PORT
      LAYER met3 ;
        RECT 0.000 148.280 4.000 148.880 ;
    END
  END rf_wr_data_o[18]
  PIN rf_wr_data_o[19]
    PORT
      LAYER met3 ;
        RECT 0.000 149.640 4.000 150.240 ;
    END
  END rf_wr_data_o[19]
  PIN rf_wr_data_o[1]
    PORT
      LAYER met3 ;
        RECT 0.000 125.160 4.000 125.760 ;
    END
  END rf_wr_data_o[1]
  PIN rf_wr_data_o[20]
    PORT
      LAYER met3 ;
        RECT 0.000 151.000 4.000 151.600 ;
    END
  END rf_wr_data_o[20]
  PIN rf_wr_data_o[21]
    PORT
      LAYER met3 ;
        RECT 0.000 152.360 4.000 152.960 ;
    END
  END rf_wr_data_o[21]
  PIN rf_wr_data_o[22]
    PORT
      LAYER met3 ;
        RECT 0.000 153.720 4.000 154.320 ;
    END
  END rf_wr_data_o[22]
  PIN rf_wr_data_o[23]
    PORT
      LAYER met3 ;
        RECT 0.000 155.080 4.000 155.680 ;
    END
  END rf_wr_data_o[23]
  PIN rf_wr_data_o[24]
    PORT
      LAYER met3 ;
        RECT 0.000 156.440 4.000 157.040 ;
    END
  END rf_wr_data_o[24]
  PIN rf_wr_data_o[25]
    PORT
      LAYER met3 ;
        RECT 0.000 157.800 4.000 158.400 ;
    END
  END rf_wr_data_o[25]
  PIN rf_wr_data_o[26]
    PORT
      LAYER met3 ;
        RECT 0.000 159.160 4.000 159.760 ;
    END
  END rf_wr_data_o[26]
  PIN rf_wr_data_o[27]
    PORT
      LAYER met3 ;
        RECT 0.000 160.520 4.000 161.120 ;
    END
  END rf_wr_data_o[27]
  PIN rf_wr_data_o[28]
    PORT
      LAYER met3 ;
        RECT 0.000 161.880 4.000 162.480 ;
    END
  END rf_wr_data_o[28]
  PIN rf_wr_data_o[29]
    PORT
      LAYER met3 ;
        RECT 0.000 163.240 4.000 163.840 ;
    END
  END rf_wr_data_o[29]
  PIN rf_wr_data_o[2]
    PORT
      LAYER met3 ;
        RECT 0.000 126.520 4.000 127.120 ;
    END
  END rf_wr_data_o[2]
  PIN rf_wr_data_o[30]
    PORT
      LAYER met3 ;
        RECT 0.000 164.600 4.000 165.200 ;
    END
  END rf_wr_data_o[30]
  PIN rf_wr_data_o[31]
    PORT
      LAYER met3 ;
        RECT 0.000 165.960 4.000 166.560 ;
    END
  END rf_wr_data_o[31]
  PIN rf_wr_data_o[3]
    PORT
      LAYER met3 ;
        RECT 0.000 127.880 4.000 128.480 ;
    END
  END rf_wr_data_o[3]
  PIN rf_wr_data_o[4]
    PORT
      LAYER met3 ;
        RECT 0.000 129.240 4.000 129.840 ;
    END
  END rf_wr_data_o[4]
  PIN rf_wr_data_o[5]
    PORT
      LAYER met3 ;
        RECT 0.000 130.600 4.000 131.200 ;
    END
  END rf_wr_data_o[5]
  PIN rf_wr_data_o[6]
    PORT
      LAYER met3 ;
        RECT 0.000 131.960 4.000 132.560 ;
    END
  END rf_wr_data_o[6]
  PIN rf_wr_data_o[7]
    PORT
      LAYER met3 ;
        RECT 0.000 133.320 4.000 133.920 ;
    END
  END rf_wr_data_o[7]
  PIN rf_wr_data_o[8]
    PORT
      LAYER met3 ;
        RECT 0.000 134.680 4.000 135.280 ;
    END
  END rf_wr_data_o[8]
  PIN rf_wr_data_o[9]
    PORT
      LAYER met3 ;
        RECT 0.000 136.040 4.000 136.640 ;
    END
  END rf_wr_data_o[9]
  PIN rf_wr_en_o
    PORT
      LAYER met3 ;
        RECT 0.000 167.320 4.000 167.920 ;
    END
  END rf_wr_en_o
  PIN rf_wr_reg_o[0]
    PORT
      LAYER met3 ;
        RECT 0.000 117.000 4.000 117.600 ;
    END
  END rf_wr_reg_o[0]
  PIN rf_wr_reg_o[1]
    PORT
      LAYER met3 ;
        RECT 0.000 118.360 4.000 118.960 ;
    END
  END rf_wr_reg_o[1]
  PIN rf_wr_reg_o[2]
    PORT
      LAYER met3 ;
        RECT 0.000 119.720 4.000 120.320 ;
    END
  END rf_wr_reg_o[2]
  PIN rf_wr_reg_o[3]
    PORT
      LAYER met3 ;
        RECT 0.000 121.080 4.000 121.680 ;
    END
  END rf_wr_reg_o[3]
  PIN rf_wr_reg_o[4]
    PORT
      LAYER met3 ;
        RECT 0.000 122.440 4.000 123.040 ;
    END
  END rf_wr_reg_o[4]
  PIN rst_ni
    PORT
      LAYER met2 ;
        RECT 99.910 496.000 100.190 500.000 ;
    END
  END rst_ni
  OBS
      LAYER li1 ;
        RECT 5.520 10.795 394.220 486.965 ;
      LAYER met1 ;
        RECT 0.070 10.640 394.220 487.120 ;
      LAYER met2 ;
        RECT 0.100 495.720 99.630 496.810 ;
        RECT 100.470 495.720 299.270 496.810 ;
        RECT 300.110 495.720 394.120 496.810 ;
        RECT 0.100 10.695 394.120 495.720 ;
      LAYER met3 ;
        RECT 4.000 460.720 396.000 487.045 ;
        RECT 4.000 459.320 395.600 460.720 ;
        RECT 4.000 456.640 396.000 459.320 ;
        RECT 4.000 455.240 395.600 456.640 ;
        RECT 4.000 452.560 396.000 455.240 ;
        RECT 4.000 451.160 395.600 452.560 ;
        RECT 4.000 448.480 396.000 451.160 ;
        RECT 4.000 447.080 395.600 448.480 ;
        RECT 4.000 444.400 396.000 447.080 ;
        RECT 4.000 443.000 395.600 444.400 ;
        RECT 4.000 440.320 396.000 443.000 ;
        RECT 4.000 438.920 395.600 440.320 ;
        RECT 4.000 436.240 396.000 438.920 ;
        RECT 4.000 434.840 395.600 436.240 ;
        RECT 4.000 432.160 396.000 434.840 ;
        RECT 4.000 430.760 395.600 432.160 ;
        RECT 4.000 428.080 396.000 430.760 ;
        RECT 4.000 426.680 395.600 428.080 ;
        RECT 4.000 424.000 396.000 426.680 ;
        RECT 4.000 422.600 395.600 424.000 ;
        RECT 4.000 419.920 396.000 422.600 ;
        RECT 4.000 418.520 395.600 419.920 ;
        RECT 4.000 415.840 396.000 418.520 ;
        RECT 4.000 414.440 395.600 415.840 ;
        RECT 4.000 411.760 396.000 414.440 ;
        RECT 4.000 410.360 395.600 411.760 ;
        RECT 4.000 407.680 396.000 410.360 ;
        RECT 4.000 406.280 395.600 407.680 ;
        RECT 4.000 403.600 396.000 406.280 ;
        RECT 4.000 402.200 395.600 403.600 ;
        RECT 4.000 399.520 396.000 402.200 ;
        RECT 4.000 398.120 395.600 399.520 ;
        RECT 4.000 396.800 396.000 398.120 ;
        RECT 4.400 395.440 396.000 396.800 ;
        RECT 4.400 394.040 395.600 395.440 ;
        RECT 4.400 391.360 396.000 394.040 ;
        RECT 4.400 389.960 395.600 391.360 ;
        RECT 4.400 387.280 396.000 389.960 ;
        RECT 4.400 385.880 395.600 387.280 ;
        RECT 4.400 383.200 396.000 385.880 ;
        RECT 4.400 381.800 395.600 383.200 ;
        RECT 4.400 379.120 396.000 381.800 ;
        RECT 4.400 377.720 395.600 379.120 ;
        RECT 4.400 375.040 396.000 377.720 ;
        RECT 4.400 373.640 395.600 375.040 ;
        RECT 4.400 370.960 396.000 373.640 ;
        RECT 4.400 369.560 395.600 370.960 ;
        RECT 4.400 366.880 396.000 369.560 ;
        RECT 4.400 365.480 395.600 366.880 ;
        RECT 4.400 362.800 396.000 365.480 ;
        RECT 4.400 361.400 395.600 362.800 ;
        RECT 4.400 358.720 396.000 361.400 ;
        RECT 4.400 357.320 395.600 358.720 ;
        RECT 4.400 354.640 396.000 357.320 ;
        RECT 4.400 353.240 395.600 354.640 ;
        RECT 4.400 350.560 396.000 353.240 ;
        RECT 4.400 349.160 395.600 350.560 ;
        RECT 4.400 346.480 396.000 349.160 ;
        RECT 4.400 345.080 395.600 346.480 ;
        RECT 4.400 342.400 396.000 345.080 ;
        RECT 4.400 341.000 395.600 342.400 ;
        RECT 4.400 338.320 396.000 341.000 ;
        RECT 4.400 336.920 395.600 338.320 ;
        RECT 4.400 334.240 396.000 336.920 ;
        RECT 4.400 332.840 395.600 334.240 ;
        RECT 4.400 330.160 396.000 332.840 ;
        RECT 4.400 328.760 395.600 330.160 ;
        RECT 4.400 326.080 396.000 328.760 ;
        RECT 4.400 324.680 395.600 326.080 ;
        RECT 4.400 322.000 396.000 324.680 ;
        RECT 4.400 320.600 395.600 322.000 ;
        RECT 4.400 317.920 396.000 320.600 ;
        RECT 4.400 316.520 395.600 317.920 ;
        RECT 4.400 313.840 396.000 316.520 ;
        RECT 4.400 312.440 395.600 313.840 ;
        RECT 4.400 309.760 396.000 312.440 ;
        RECT 4.400 308.360 395.600 309.760 ;
        RECT 4.400 305.680 396.000 308.360 ;
        RECT 4.400 304.280 395.600 305.680 ;
        RECT 4.400 301.600 396.000 304.280 ;
        RECT 4.400 300.200 395.600 301.600 ;
        RECT 4.400 297.520 396.000 300.200 ;
        RECT 4.400 296.120 395.600 297.520 ;
        RECT 4.400 293.440 396.000 296.120 ;
        RECT 4.400 292.040 395.600 293.440 ;
        RECT 4.400 289.360 396.000 292.040 ;
        RECT 4.400 287.960 395.600 289.360 ;
        RECT 4.400 285.280 396.000 287.960 ;
        RECT 4.400 283.880 395.600 285.280 ;
        RECT 4.400 281.200 396.000 283.880 ;
        RECT 4.400 279.800 395.600 281.200 ;
        RECT 4.400 277.120 396.000 279.800 ;
        RECT 4.400 275.720 395.600 277.120 ;
        RECT 4.400 273.040 396.000 275.720 ;
        RECT 4.400 271.640 395.600 273.040 ;
        RECT 4.400 268.960 396.000 271.640 ;
        RECT 4.400 267.560 395.600 268.960 ;
        RECT 4.400 264.880 396.000 267.560 ;
        RECT 4.400 263.480 395.600 264.880 ;
        RECT 4.400 260.800 396.000 263.480 ;
        RECT 4.400 259.400 395.600 260.800 ;
        RECT 4.400 256.720 396.000 259.400 ;
        RECT 4.400 255.320 395.600 256.720 ;
        RECT 4.400 252.640 396.000 255.320 ;
        RECT 4.400 251.240 395.600 252.640 ;
        RECT 4.400 248.560 396.000 251.240 ;
        RECT 4.400 247.160 395.600 248.560 ;
        RECT 4.400 244.480 396.000 247.160 ;
        RECT 4.400 243.080 395.600 244.480 ;
        RECT 4.400 240.400 396.000 243.080 ;
        RECT 4.400 239.000 395.600 240.400 ;
        RECT 4.400 236.320 396.000 239.000 ;
        RECT 4.400 234.920 395.600 236.320 ;
        RECT 4.400 232.240 396.000 234.920 ;
        RECT 4.400 230.840 395.600 232.240 ;
        RECT 4.400 228.160 396.000 230.840 ;
        RECT 4.400 226.760 395.600 228.160 ;
        RECT 4.400 224.080 396.000 226.760 ;
        RECT 4.400 222.680 395.600 224.080 ;
        RECT 4.400 220.000 396.000 222.680 ;
        RECT 4.400 218.600 395.600 220.000 ;
        RECT 4.400 215.920 396.000 218.600 ;
        RECT 4.400 214.520 395.600 215.920 ;
        RECT 4.400 211.840 396.000 214.520 ;
        RECT 4.400 210.440 395.600 211.840 ;
        RECT 4.400 207.760 396.000 210.440 ;
        RECT 4.400 206.360 395.600 207.760 ;
        RECT 4.400 203.680 396.000 206.360 ;
        RECT 4.400 202.280 395.600 203.680 ;
        RECT 4.400 199.600 396.000 202.280 ;
        RECT 4.400 198.200 395.600 199.600 ;
        RECT 4.400 195.520 396.000 198.200 ;
        RECT 4.400 194.120 395.600 195.520 ;
        RECT 4.400 191.440 396.000 194.120 ;
        RECT 4.400 190.040 395.600 191.440 ;
        RECT 4.400 187.360 396.000 190.040 ;
        RECT 4.400 185.960 395.600 187.360 ;
        RECT 4.400 183.280 396.000 185.960 ;
        RECT 4.400 181.880 395.600 183.280 ;
        RECT 4.400 179.200 396.000 181.880 ;
        RECT 4.400 177.800 395.600 179.200 ;
        RECT 4.400 175.120 396.000 177.800 ;
        RECT 4.400 173.720 395.600 175.120 ;
        RECT 4.400 171.040 396.000 173.720 ;
        RECT 4.400 169.640 395.600 171.040 ;
        RECT 4.400 166.960 396.000 169.640 ;
        RECT 4.400 165.560 395.600 166.960 ;
        RECT 4.400 162.880 396.000 165.560 ;
        RECT 4.400 161.480 395.600 162.880 ;
        RECT 4.400 158.800 396.000 161.480 ;
        RECT 4.400 157.400 395.600 158.800 ;
        RECT 4.400 154.720 396.000 157.400 ;
        RECT 4.400 153.320 395.600 154.720 ;
        RECT 4.400 150.640 396.000 153.320 ;
        RECT 4.400 149.240 395.600 150.640 ;
        RECT 4.400 146.560 396.000 149.240 ;
        RECT 4.400 145.160 395.600 146.560 ;
        RECT 4.400 142.480 396.000 145.160 ;
        RECT 4.400 141.080 395.600 142.480 ;
        RECT 4.400 138.400 396.000 141.080 ;
        RECT 4.400 137.000 395.600 138.400 ;
        RECT 4.400 134.320 396.000 137.000 ;
        RECT 4.400 132.920 395.600 134.320 ;
        RECT 4.400 130.240 396.000 132.920 ;
        RECT 4.400 128.840 395.600 130.240 ;
        RECT 4.400 126.160 396.000 128.840 ;
        RECT 4.400 124.760 395.600 126.160 ;
        RECT 4.400 122.080 396.000 124.760 ;
        RECT 4.400 120.680 395.600 122.080 ;
        RECT 4.400 118.000 396.000 120.680 ;
        RECT 4.400 116.600 395.600 118.000 ;
        RECT 4.400 113.920 396.000 116.600 ;
        RECT 4.400 112.520 395.600 113.920 ;
        RECT 4.400 109.840 396.000 112.520 ;
        RECT 4.400 108.440 395.600 109.840 ;
        RECT 4.400 105.760 396.000 108.440 ;
        RECT 4.400 104.360 395.600 105.760 ;
        RECT 4.400 103.000 396.000 104.360 ;
        RECT 4.000 101.680 396.000 103.000 ;
        RECT 4.000 100.280 395.600 101.680 ;
        RECT 4.000 97.600 396.000 100.280 ;
        RECT 4.000 96.200 395.600 97.600 ;
        RECT 4.000 93.520 396.000 96.200 ;
        RECT 4.000 92.120 395.600 93.520 ;
        RECT 4.000 89.440 396.000 92.120 ;
        RECT 4.000 88.040 395.600 89.440 ;
        RECT 4.000 85.360 396.000 88.040 ;
        RECT 4.000 83.960 395.600 85.360 ;
        RECT 4.000 81.280 396.000 83.960 ;
        RECT 4.000 79.880 395.600 81.280 ;
        RECT 4.000 77.200 396.000 79.880 ;
        RECT 4.000 75.800 395.600 77.200 ;
        RECT 4.000 73.120 396.000 75.800 ;
        RECT 4.000 71.720 395.600 73.120 ;
        RECT 4.000 69.040 396.000 71.720 ;
        RECT 4.000 67.640 395.600 69.040 ;
        RECT 4.000 64.960 396.000 67.640 ;
        RECT 4.000 63.560 395.600 64.960 ;
        RECT 4.000 60.880 396.000 63.560 ;
        RECT 4.000 59.480 395.600 60.880 ;
        RECT 4.000 56.800 396.000 59.480 ;
        RECT 4.000 55.400 395.600 56.800 ;
        RECT 4.000 52.720 396.000 55.400 ;
        RECT 4.000 51.320 395.600 52.720 ;
        RECT 4.000 48.640 396.000 51.320 ;
        RECT 4.000 47.240 395.600 48.640 ;
        RECT 4.000 44.560 396.000 47.240 ;
        RECT 4.000 43.160 395.600 44.560 ;
        RECT 4.000 40.480 396.000 43.160 ;
        RECT 4.000 39.080 395.600 40.480 ;
        RECT 4.000 10.715 396.000 39.080 ;
      LAYER met4 ;
        RECT 9.495 96.735 20.640 430.265 ;
        RECT 23.040 96.735 23.940 430.265 ;
        RECT 26.340 96.735 174.240 430.265 ;
        RECT 176.640 96.735 177.540 430.265 ;
        RECT 179.940 96.735 196.585 430.265 ;
      LAYER met5 ;
        RECT 33.700 339.590 181.580 342.500 ;
        RECT 33.700 286.500 181.580 331.490 ;
  END
END core
END LIBRARY

